VERSION 5.7 ;
  NOWIREEXTENSIONATPIN ON ;
  DIVIDERCHAR "/" ;
  BUSBITCHARS "[]" ;
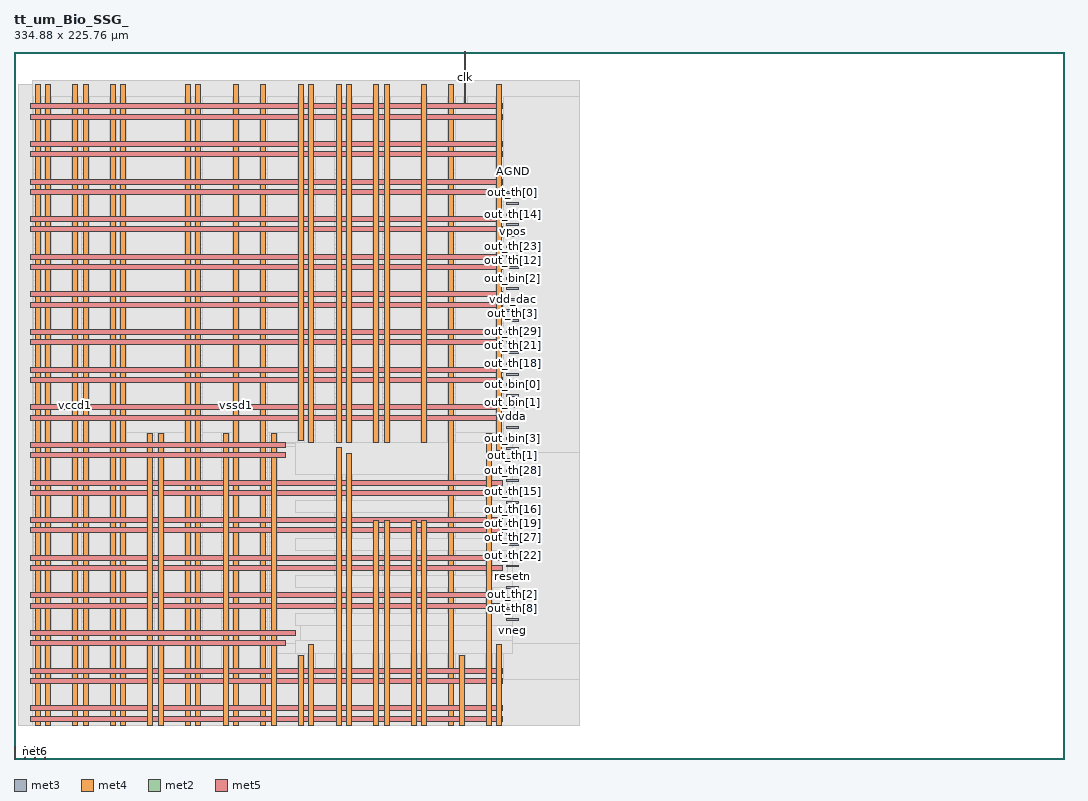
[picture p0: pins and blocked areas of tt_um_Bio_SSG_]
MACRO tt_um_Bio_SSG_
  CLASS BLOCK ;
  FOREIGN tt_um_Bio_SSG_ ;
  ORIGIN 0.000 0.000 ;
  SIZE 334.880 BY 225.760 ;
  PIN AGND
    DIRECTION INOUT ;
    USE SIGNAL ;
    ANTENNADIFFAREA 0.434700 ;
    PORT
      LAYER met3 ;
        RECT 157.000 187.040 161.000 187.640 ;
    END
  END AGND
  PIN clk
    DIRECTION INPUT ;
    USE SIGNAL ;
    ANTENNAGATEAREA 0.852000 ;
    ANTENNADIFFAREA 0.434700 ;
    PORT
      LAYER met4 ;
        RECT 143.830 208.950 144.130 225.760 ;
    END
  END clk
  PIN cm1
    DIRECTION INOUT ;
    USE SIGNAL ;
    PORT
      LAYER met2 ;
        RECT 0.090 0.000 0.370 4.000 ;
    END
  END cm1
  PIN cm2
    DIRECTION INOUT ;
    USE SIGNAL ;
    PORT
      LAYER met2 ;
        RECT 3.310 0.000 3.590 4.000 ;
    END
  END cm2
  PIN net6
    DIRECTION INOUT ;
    USE SIGNAL ;
    PORT
      LAYER met2 ;
        RECT 6.530 0.000 6.810 4.000 ;
    END
  END net6
  PIN net7
    DIRECTION INOUT ;
    USE SIGNAL ;
    PORT
      LAYER met2 ;
        RECT 9.750 0.000 10.030 4.000 ;
    END
  END net7
  PIN out_bin[0]
    DIRECTION OUTPUT ;
    USE SIGNAL ;
    ANTENNADIFFAREA 0.445500 ;
    PORT
      LAYER met3 ;
        RECT 157.000 119.040 161.000 119.640 ;
    END
  END out_bin[0]
  PIN out_bin[1]
    DIRECTION OUTPUT ;
    USE SIGNAL ;
    ANTENNADIFFAREA 0.445500 ;
    PORT
      LAYER met3 ;
        RECT 157.000 115.640 161.000 116.240 ;
    END
  END out_bin[1]
  PIN out_bin[2]
    DIRECTION OUTPUT ;
    USE SIGNAL ;
    ANTENNADIFFAREA 0.445500 ;
    PORT
      LAYER met3 ;
        RECT 157.000 153.040 161.000 153.640 ;
    END
  END out_bin[2]
  PIN out_bin[3]
    DIRECTION OUTPUT ;
    USE SIGNAL ;
    ANTENNADIFFAREA 0.445500 ;
    PORT
      LAYER met3 ;
        RECT 157.000 102.040 161.000 102.640 ;
    END
  END out_bin[3]
  PIN out_th[0]
    DIRECTION OUTPUT ;
    USE SIGNAL ;
    ANTENNADIFFAREA 0.445500 ;
    PORT
      LAYER met3 ;
        RECT 157.000 180.240 161.000 180.840 ;
    END
  END out_th[0]
  PIN out_th[10]
    DIRECTION OUTPUT ;
    USE SIGNAL ;
    ANTENNADIFFAREA 0.445500 ;
    PORT
      LAYER met3 ;
        RECT 157.000 132.640 161.000 133.240 ;
    END
  END out_th[10]
  PIN out_th[11]
    DIRECTION OUTPUT ;
    USE SIGNAL ;
    ANTENNADIFFAREA 0.445500 ;
    PORT
      LAYER met3 ;
        RECT 157.000 95.240 161.000 95.840 ;
    END
  END out_th[11]
  PIN out_th[12]
    DIRECTION OUTPUT ;
    USE SIGNAL ;
    ANTENNADIFFAREA 0.445500 ;
    PORT
      LAYER met3 ;
        RECT 157.000 156.440 161.000 157.040 ;
    END
  END out_th[12]
  PIN out_th[13]
    DIRECTION OUTPUT ;
    USE SIGNAL ;
    ANTENNADIFFAREA 0.445500 ;
    PORT
      LAYER met3 ;
        RECT 157.000 88.440 161.000 89.040 ;
    END
  END out_th[13]
  PIN out_th[14]
    DIRECTION OUTPUT ;
    USE SIGNAL ;
    ANTENNADIFFAREA 0.445500 ;
    PORT
      LAYER met3 ;
        RECT 157.000 173.440 161.000 174.040 ;
    END
  END out_th[14]
  PIN out_th[15]
    DIRECTION OUTPUT ;
    USE SIGNAL ;
    ANTENNADIFFAREA 0.445500 ;
    PORT
      LAYER met3 ;
        RECT 157.000 85.040 161.000 85.640 ;
    END
  END out_th[15]
  PIN out_th[16]
    DIRECTION OUTPUT ;
    USE SIGNAL ;
    ANTENNADIFFAREA 0.445500 ;
    PORT
      LAYER met3 ;
        RECT 157.000 81.640 161.000 82.240 ;
    END
  END out_th[16]
  PIN out_th[17]
    DIRECTION OUTPUT ;
    USE SIGNAL ;
    ANTENNADIFFAREA 0.445500 ;
    PORT
      LAYER met3 ;
        RECT 157.000 159.840 161.000 160.440 ;
    END
  END out_th[17]
  PIN out_th[18]
    DIRECTION OUTPUT ;
    USE SIGNAL ;
    ANTENNADIFFAREA 0.445500 ;
    PORT
      LAYER met3 ;
        RECT 157.000 125.840 161.000 126.440 ;
    END
  END out_th[18]
  PIN out_th[19]
    DIRECTION OUTPUT ;
    USE SIGNAL ;
    ANTENNADIFFAREA 0.445500 ;
    PORT
      LAYER met3 ;
        RECT 157.000 74.840 161.000 75.440 ;
    END
  END out_th[19]
  PIN out_th[1]
    DIRECTION OUTPUT ;
    USE SIGNAL ;
    ANTENNADIFFAREA 0.445500 ;
    PORT
      LAYER met3 ;
        RECT 157.000 98.640 161.000 99.240 ;
    END
  END out_th[1]
  PIN out_th[20]
    DIRECTION OUTPUT ;
    USE SIGNAL ;
    ANTENNADIFFAREA 0.445500 ;
    PORT
      LAYER met3 ;
        RECT 157.000 112.240 161.000 112.840 ;
    END
  END out_th[20]
  PIN out_th[21]
    DIRECTION OUTPUT ;
    USE SIGNAL ;
    ANTENNADIFFAREA 0.445500 ;
    PORT
      LAYER met3 ;
        RECT 157.000 129.240 161.000 129.840 ;
    END
  END out_th[21]
  PIN out_th[22]
    DIRECTION OUTPUT ;
    USE SIGNAL ;
    ANTENNADIFFAREA 0.445500 ;
    PORT
      LAYER met3 ;
        RECT 157.000 64.640 161.000 65.240 ;
    END
  END out_th[22]
  PIN out_th[23]
    DIRECTION OUTPUT ;
    USE SIGNAL ;
    ANTENNADIFFAREA 0.445500 ;
    PORT
      LAYER met3 ;
        RECT 157.000 163.240 161.000 163.840 ;
    END
  END out_th[23]
  PIN out_th[24]
    DIRECTION OUTPUT ;
    USE SIGNAL ;
    ANTENNADIFFAREA 0.445500 ;
    PORT
      LAYER met3 ;
        RECT 157.000 61.240 161.000 61.840 ;
    END
  END out_th[24]
  PIN out_th[25]
    DIRECTION OUTPUT ;
    USE SIGNAL ;
    ANTENNADIFFAREA 0.445500 ;
    PORT
      LAYER met3 ;
        RECT 157.000 176.840 161.000 177.440 ;
    END
  END out_th[25]
  PIN out_th[26]
    DIRECTION OUTPUT ;
    USE SIGNAL ;
    ANTENNADIFFAREA 0.445500 ;
    PORT
      LAYER met3 ;
        RECT 157.000 78.240 161.000 78.840 ;
    END
  END out_th[26]
  PIN out_th[27]
    DIRECTION OUTPUT ;
    USE SIGNAL ;
    ANTENNADIFFAREA 0.445500 ;
    PORT
      LAYER met3 ;
        RECT 157.000 68.040 161.000 68.640 ;
    END
  END out_th[27]
  PIN out_th[28]
    DIRECTION OUTPUT ;
    USE SIGNAL ;
    ANTENNADIFFAREA 0.445500 ;
    PORT
      LAYER met3 ;
        RECT 157.000 91.840 161.000 92.440 ;
    END
  END out_th[28]
  PIN out_th[29]
    DIRECTION OUTPUT ;
    USE SIGNAL ;
    ANTENNADIFFAREA 0.445500 ;
    PORT
      LAYER met3 ;
        RECT 157.000 136.040 161.000 136.640 ;
    END
  END out_th[29]
  PIN out_th[2]
    DIRECTION OUTPUT ;
    USE SIGNAL ;
    ANTENNADIFFAREA 0.445500 ;
    PORT
      LAYER met3 ;
        RECT 157.000 54.440 161.000 55.040 ;
    END
  END out_th[2]
  PIN out_th[30]
    DIRECTION OUTPUT ;
    USE SIGNAL ;
    ANTENNADIFFAREA 0.445500 ;
    PORT
      LAYER met3 ;
        RECT 157.000 105.440 161.000 106.040 ;
    END
  END out_th[30]
  PIN out_th[31]
    DIRECTION OUTPUT ;
    USE SIGNAL ;
    ANTENNADIFFAREA 0.445500 ;
    PORT
      LAYER met3 ;
        RECT 157.000 51.040 161.000 51.640 ;
    END
  END out_th[31]
  PIN out_th[3]
    DIRECTION OUTPUT ;
    USE SIGNAL ;
    ANTENNADIFFAREA 0.445500 ;
    PORT
      LAYER met3 ;
        RECT 157.000 139.440 161.000 140.040 ;
    END
  END out_th[3]
  PIN out_th[4]
    DIRECTION OUTPUT ;
    USE SIGNAL ;
    ANTENNADIFFAREA 0.445500 ;
    PORT
      LAYER met3 ;
        RECT 157.000 166.640 161.000 167.240 ;
    END
  END out_th[4]
  PIN out_th[5]
    DIRECTION OUTPUT ;
    USE SIGNAL ;
    ANTENNADIFFAREA 0.445500 ;
    PORT
      LAYER met3 ;
        RECT 157.000 71.440 161.000 72.040 ;
    END
  END out_th[5]
  PIN out_th[6]
    DIRECTION OUTPUT ;
    USE SIGNAL ;
    ANTENNADIFFAREA 0.445500 ;
    PORT
      LAYER met3 ;
        RECT 157.000 122.440 161.000 123.040 ;
    END
  END out_th[6]
  PIN out_th[7]
    DIRECTION OUTPUT ;
    USE SIGNAL ;
    ANTENNADIFFAREA 0.445500 ;
    PORT
      LAYER met3 ;
        RECT 157.000 142.840 161.000 143.440 ;
    END
  END out_th[7]
  PIN out_th[8]
    DIRECTION OUTPUT ;
    USE SIGNAL ;
    ANTENNADIFFAREA 0.445500 ;
    PORT
      LAYER met3 ;
        RECT 157.000 47.640 161.000 48.240 ;
    END
  END out_th[8]
  PIN out_th[9]
    DIRECTION OUTPUT ;
    USE SIGNAL ;
    ANTENNADIFFAREA 0.445500 ;
    PORT
      LAYER met3 ;
        RECT 157.000 44.240 161.000 44.840 ;
    END
  END out_th[9]
  PIN resetn
    DIRECTION INPUT ;
    USE SIGNAL ;
    ANTENNAGATEAREA 0.196500 ;
    ANTENNADIFFAREA 0.434700 ;
    PORT
      LAYER met3 ;
        RECT 157.000 57.840 161.000 58.440 ;
    END
  END resetn
  PIN vccd1
    DIRECTION INOUT ;
    USE POWER ;
    PORT
      LAYER met4 ;
        RECT 6.720 10.640 8.320 215.120 ;
    END
    PORT
      LAYER met4 ;
        RECT 18.720 10.640 20.320 215.120 ;
    END
    PORT
      LAYER met4 ;
        RECT 30.720 10.640 32.320 215.120 ;
    END
    PORT
      LAYER met4 ;
        RECT 42.720 10.640 44.320 103.720 ;
    END
    PORT
      LAYER met4 ;
        RECT 54.720 10.640 56.320 215.120 ;
    END
    PORT
      LAYER met4 ;
        RECT 66.720 10.640 68.320 103.720 ;
    END
    PORT
      LAYER met4 ;
        RECT 78.720 10.640 80.320 215.120 ;
    END
    PORT
      LAYER met4 ;
        RECT 90.720 10.640 92.320 33.160 ;
    END
    PORT
      LAYER met4 ;
        RECT 90.720 101.480 92.320 215.120 ;
    END
    PORT
      LAYER met4 ;
        RECT 102.720 10.640 104.320 99.405 ;
    END
    PORT
      LAYER met4 ;
        RECT 102.720 100.935 104.320 215.120 ;
    END
    PORT
      LAYER met4 ;
        RECT 114.720 10.640 116.320 76.120 ;
    END
    PORT
      LAYER met4 ;
        RECT 114.720 100.935 116.320 215.120 ;
    END
    PORT
      LAYER met4 ;
        RECT 126.720 10.640 128.320 76.120 ;
    END
    PORT
      LAYER met4 ;
        RECT 138.720 10.640 140.320 215.120 ;
    END
    PORT
      LAYER met4 ;
        RECT 150.720 10.640 152.320 103.720 ;
    END
    PORT
      LAYER met5 ;
        RECT 5.280 12.080 155.720 13.680 ;
    END
    PORT
      LAYER met5 ;
        RECT 5.280 24.080 155.720 25.680 ;
    END
    PORT
      LAYER met5 ;
        RECT 5.280 36.080 86.620 37.680 ;
    END
    PORT
      LAYER met5 ;
        RECT 5.280 48.080 155.720 49.680 ;
    END
    PORT
      LAYER met5 ;
        RECT 5.280 60.080 155.720 61.680 ;
    END
    PORT
      LAYER met5 ;
        RECT 5.280 72.080 155.720 73.680 ;
    END
    PORT
      LAYER met5 ;
        RECT 5.280 84.080 155.720 85.680 ;
    END
    PORT
      LAYER met5 ;
        RECT 5.280 96.080 86.620 97.680 ;
    END
    PORT
      LAYER met5 ;
        RECT 5.280 108.080 155.720 109.680 ;
    END
    PORT
      LAYER met5 ;
        RECT 5.280 120.080 155.720 121.680 ;
    END
    PORT
      LAYER met5 ;
        RECT 5.280 132.080 155.720 133.680 ;
    END
    PORT
      LAYER met5 ;
        RECT 5.280 144.080 155.720 145.680 ;
    END
    PORT
      LAYER met5 ;
        RECT 5.280 156.080 155.720 157.680 ;
    END
    PORT
      LAYER met5 ;
        RECT 5.280 168.080 155.720 169.680 ;
    END
    PORT
      LAYER met5 ;
        RECT 5.280 180.080 155.720 181.680 ;
    END
    PORT
      LAYER met5 ;
        RECT 5.280 192.080 155.720 193.680 ;
    END
    PORT
      LAYER met5 ;
        RECT 5.280 204.080 155.720 205.680 ;
    END
  END vccd1
  PIN vdd_dac
    DIRECTION INOUT ;
    USE SIGNAL ;
    ANTENNADIFFAREA 0.434700 ;
    PORT
      LAYER met3 ;
        RECT 157.000 146.240 161.000 146.840 ;
    END
  END vdd_dac
  PIN vdda
    DIRECTION INOUT ;
    USE SIGNAL ;
    PORT
      LAYER met3 ;
        RECT 157.000 108.840 161.000 109.440 ;
    END
  END vdda
  PIN vneg
    DIRECTION OUTPUT ;
    USE SIGNAL ;
    ANTENNADIFFAREA 0.445500 ;
    PORT
      LAYER met3 ;
        RECT 157.000 40.840 161.000 41.440 ;
    END
  END vneg
  PIN vpos
    DIRECTION OUTPUT ;
    USE SIGNAL ;
    ANTENNADIFFAREA 0.445500 ;
    PORT
      LAYER met3 ;
        RECT 157.000 170.040 161.000 170.640 ;
    END
  END vpos
  PIN vss
    DIRECTION INOUT ;
    USE SIGNAL ;
    ANTENNADIFFAREA 0.869400 ;
    PORT
      LAYER met3 ;
        RECT 157.000 149.640 161.000 150.240 ;
    END
  END vss
  PIN vssd1
    DIRECTION INOUT ;
    USE GROUND ;
    PORT
      LAYER met4 ;
        RECT 10.020 10.640 11.620 215.120 ;
    END
    PORT
      LAYER met4 ;
        RECT 22.020 10.640 23.620 215.120 ;
    END
    PORT
      LAYER met4 ;
        RECT 34.020 10.640 35.620 215.120 ;
    END
    PORT
      LAYER met4 ;
        RECT 46.020 10.640 47.620 103.720 ;
    END
    PORT
      LAYER met4 ;
        RECT 58.020 10.640 59.620 215.120 ;
    END
    PORT
      LAYER met4 ;
        RECT 70.020 10.640 71.620 215.120 ;
    END
    PORT
      LAYER met4 ;
        RECT 82.020 10.640 83.620 103.720 ;
    END
    PORT
      LAYER met4 ;
        RECT 94.020 10.640 95.620 36.360 ;
    END
    PORT
      LAYER met4 ;
        RECT 94.020 100.935 95.620 215.120 ;
    END
    PORT
      LAYER met4 ;
        RECT 106.020 10.640 107.620 97.570 ;
    END
    PORT
      LAYER met4 ;
        RECT 106.020 100.935 107.620 215.120 ;
    END
    PORT
      LAYER met4 ;
        RECT 118.020 10.640 119.620 76.120 ;
    END
    PORT
      LAYER met4 ;
        RECT 118.020 100.935 119.620 215.120 ;
    END
    PORT
      LAYER met4 ;
        RECT 130.020 10.640 131.620 76.120 ;
    END
    PORT
      LAYER met4 ;
        RECT 130.020 100.935 131.620 215.120 ;
    END
    PORT
      LAYER met4 ;
        RECT 142.020 10.640 143.620 33.160 ;
    END
    PORT
      LAYER met4 ;
        RECT 154.020 10.640 155.620 36.360 ;
    END
    PORT
      LAYER met4 ;
        RECT 154.020 98.280 155.620 215.120 ;
    END
    PORT
      LAYER met5 ;
        RECT 5.280 15.380 155.720 16.980 ;
    END
    PORT
      LAYER met5 ;
        RECT 5.280 27.380 155.720 28.980 ;
    END
    PORT
      LAYER met5 ;
        RECT 5.280 39.380 89.820 40.980 ;
    END
    PORT
      LAYER met5 ;
        RECT 5.280 51.380 155.720 52.980 ;
    END
    PORT
      LAYER met5 ;
        RECT 5.280 63.380 155.720 64.980 ;
    END
    PORT
      LAYER met5 ;
        RECT 5.280 75.380 155.720 76.980 ;
    END
    PORT
      LAYER met5 ;
        RECT 5.280 87.380 155.720 88.980 ;
    END
    PORT
      LAYER met5 ;
        RECT 5.280 99.380 86.620 100.980 ;
    END
    PORT
      LAYER met5 ;
        RECT 5.280 111.380 155.720 112.980 ;
    END
    PORT
      LAYER met5 ;
        RECT 5.280 123.380 155.720 124.980 ;
    END
    PORT
      LAYER met5 ;
        RECT 5.280 135.380 155.720 136.980 ;
    END
    PORT
      LAYER met5 ;
        RECT 5.280 147.380 155.720 148.980 ;
    END
    PORT
      LAYER met5 ;
        RECT 5.280 159.380 155.720 160.980 ;
    END
    PORT
      LAYER met5 ;
        RECT 5.280 171.380 155.720 172.980 ;
    END
    PORT
      LAYER met5 ;
        RECT 5.280 183.380 155.720 184.980 ;
    END
    PORT
      LAYER met5 ;
        RECT 5.280 195.380 155.720 196.980 ;
    END
    PORT
      LAYER met5 ;
        RECT 5.280 207.380 155.720 208.980 ;
    END
  END vssd1
  OBS
      LAYER li1 ;
        RECT 5.520 10.795 155.480 214.965 ;
      LAYER met1 ;
        RECT 1.450 10.640 159.550 215.120 ;
      LAYER met2 ;
        RECT 1.480 10.695 160.910 215.065 ;
      LAYER met3 ;
        RECT 5.790 188.040 180.380 216.305 ;
        RECT 5.790 186.640 156.600 188.040 ;
        RECT 161.400 186.640 180.380 188.040 ;
        RECT 5.790 181.240 180.380 186.640 ;
        RECT 5.790 179.840 156.600 181.240 ;
        RECT 161.400 179.840 180.380 181.240 ;
        RECT 5.790 177.840 180.380 179.840 ;
        RECT 5.790 176.440 156.600 177.840 ;
        RECT 161.400 176.440 180.380 177.840 ;
        RECT 5.790 174.440 180.380 176.440 ;
        RECT 5.790 173.040 156.600 174.440 ;
        RECT 161.400 173.040 180.380 174.440 ;
        RECT 5.790 171.040 180.380 173.040 ;
        RECT 5.790 169.640 156.600 171.040 ;
        RECT 161.400 169.640 180.380 171.040 ;
        RECT 5.790 167.640 180.380 169.640 ;
        RECT 5.790 166.240 156.600 167.640 ;
        RECT 161.400 166.240 180.380 167.640 ;
        RECT 5.790 164.240 180.380 166.240 ;
        RECT 5.790 162.840 156.600 164.240 ;
        RECT 161.400 162.840 180.380 164.240 ;
        RECT 5.790 160.840 180.380 162.840 ;
        RECT 5.790 159.440 156.600 160.840 ;
        RECT 161.400 159.440 180.380 160.840 ;
        RECT 5.790 157.440 180.380 159.440 ;
        RECT 5.790 156.040 156.600 157.440 ;
        RECT 161.400 156.040 180.380 157.440 ;
        RECT 5.790 154.040 180.380 156.040 ;
        RECT 5.790 152.640 156.600 154.040 ;
        RECT 161.400 152.640 180.380 154.040 ;
        RECT 5.790 150.640 180.380 152.640 ;
        RECT 5.790 149.240 156.600 150.640 ;
        RECT 161.400 149.240 180.380 150.640 ;
        RECT 5.790 147.240 180.380 149.240 ;
        RECT 5.790 145.840 156.600 147.240 ;
        RECT 161.400 145.840 180.380 147.240 ;
        RECT 5.790 143.840 180.380 145.840 ;
        RECT 5.790 142.440 156.600 143.840 ;
        RECT 161.400 142.440 180.380 143.840 ;
        RECT 5.790 140.440 180.380 142.440 ;
        RECT 5.790 139.040 156.600 140.440 ;
        RECT 161.400 139.040 180.380 140.440 ;
        RECT 5.790 137.040 180.380 139.040 ;
        RECT 5.790 135.640 156.600 137.040 ;
        RECT 161.400 135.640 180.380 137.040 ;
        RECT 5.790 133.640 180.380 135.640 ;
        RECT 5.790 132.240 156.600 133.640 ;
        RECT 161.400 132.240 180.380 133.640 ;
        RECT 5.790 130.240 180.380 132.240 ;
        RECT 5.790 128.840 156.600 130.240 ;
        RECT 161.400 128.840 180.380 130.240 ;
        RECT 5.790 126.840 180.380 128.840 ;
        RECT 5.790 125.440 156.600 126.840 ;
        RECT 161.400 125.440 180.380 126.840 ;
        RECT 5.790 123.440 180.380 125.440 ;
        RECT 5.790 122.040 156.600 123.440 ;
        RECT 161.400 122.040 180.380 123.440 ;
        RECT 5.790 120.040 180.380 122.040 ;
        RECT 5.790 118.640 156.600 120.040 ;
        RECT 161.400 118.640 180.380 120.040 ;
        RECT 5.790 116.640 180.380 118.640 ;
        RECT 5.790 115.240 156.600 116.640 ;
        RECT 161.400 115.240 180.380 116.640 ;
        RECT 5.790 113.240 180.380 115.240 ;
        RECT 5.790 111.840 156.600 113.240 ;
        RECT 161.400 111.840 180.380 113.240 ;
        RECT 5.790 109.840 180.380 111.840 ;
        RECT 5.790 108.440 156.600 109.840 ;
        RECT 161.400 108.440 180.380 109.840 ;
        RECT 5.790 106.440 180.380 108.440 ;
        RECT 5.790 105.040 156.600 106.440 ;
        RECT 161.400 105.040 180.380 106.440 ;
        RECT 5.790 103.040 180.380 105.040 ;
        RECT 5.790 101.640 156.600 103.040 ;
        RECT 161.400 101.640 180.380 103.040 ;
        RECT 5.790 99.640 180.380 101.640 ;
        RECT 5.790 98.240 156.600 99.640 ;
        RECT 161.400 98.240 180.380 99.640 ;
        RECT 5.790 96.240 180.380 98.240 ;
        RECT 5.790 94.840 156.600 96.240 ;
        RECT 161.400 94.840 180.380 96.240 ;
        RECT 5.790 92.840 180.380 94.840 ;
        RECT 5.790 91.440 156.600 92.840 ;
        RECT 161.400 91.440 180.380 92.840 ;
        RECT 5.790 89.440 180.380 91.440 ;
        RECT 5.790 88.040 156.600 89.440 ;
        RECT 161.400 88.040 180.380 89.440 ;
        RECT 5.790 86.040 180.380 88.040 ;
        RECT 5.790 84.640 156.600 86.040 ;
        RECT 161.400 84.640 180.380 86.040 ;
        RECT 5.790 82.640 180.380 84.640 ;
        RECT 5.790 81.240 156.600 82.640 ;
        RECT 161.400 81.240 180.380 82.640 ;
        RECT 5.790 79.240 180.380 81.240 ;
        RECT 5.790 77.840 156.600 79.240 ;
        RECT 161.400 77.840 180.380 79.240 ;
        RECT 5.790 75.840 180.380 77.840 ;
        RECT 5.790 74.440 156.600 75.840 ;
        RECT 161.400 74.440 180.380 75.840 ;
        RECT 5.790 72.440 180.380 74.440 ;
        RECT 5.790 71.040 156.600 72.440 ;
        RECT 161.400 71.040 180.380 72.440 ;
        RECT 5.790 69.040 180.380 71.040 ;
        RECT 5.790 67.640 156.600 69.040 ;
        RECT 161.400 67.640 180.380 69.040 ;
        RECT 5.790 65.640 180.380 67.640 ;
        RECT 5.790 64.240 156.600 65.640 ;
        RECT 161.400 64.240 180.380 65.640 ;
        RECT 5.790 62.240 180.380 64.240 ;
        RECT 5.790 60.840 156.600 62.240 ;
        RECT 161.400 60.840 180.380 62.240 ;
        RECT 5.790 58.840 180.380 60.840 ;
        RECT 5.790 57.440 156.600 58.840 ;
        RECT 161.400 57.440 180.380 58.840 ;
        RECT 5.790 55.440 180.380 57.440 ;
        RECT 5.790 54.040 156.600 55.440 ;
        RECT 161.400 54.040 180.380 55.440 ;
        RECT 5.790 52.040 180.380 54.040 ;
        RECT 5.790 50.640 156.600 52.040 ;
        RECT 161.400 50.640 180.380 52.040 ;
        RECT 5.790 48.640 180.380 50.640 ;
        RECT 5.790 47.240 156.600 48.640 ;
        RECT 161.400 47.240 180.380 48.640 ;
        RECT 5.790 45.240 180.380 47.240 ;
        RECT 5.790 43.840 156.600 45.240 ;
        RECT 161.400 43.840 180.380 45.240 ;
        RECT 5.790 41.840 180.380 43.840 ;
        RECT 5.790 40.440 156.600 41.840 ;
        RECT 161.400 40.440 180.380 41.840 ;
        RECT 5.790 10.715 180.380 40.440 ;
      LAYER met4 ;
        RECT 5.815 25.335 6.320 211.200 ;
        RECT 8.720 25.335 9.620 211.200 ;
        RECT 12.020 25.335 18.320 211.200 ;
        RECT 20.720 25.335 21.620 211.200 ;
        RECT 24.020 25.335 30.320 211.200 ;
        RECT 32.720 25.335 33.620 211.200 ;
        RECT 36.020 104.120 54.320 211.200 ;
        RECT 36.020 25.335 42.320 104.120 ;
        RECT 44.720 25.335 45.620 104.120 ;
        RECT 48.020 25.335 54.320 104.120 ;
        RECT 56.720 25.335 57.620 211.200 ;
        RECT 60.020 104.120 69.620 211.200 ;
        RECT 60.020 25.335 66.320 104.120 ;
        RECT 68.720 25.335 69.620 104.120 ;
        RECT 72.020 25.335 78.320 211.200 ;
        RECT 80.720 104.120 90.320 211.200 ;
        RECT 80.720 25.335 81.620 104.120 ;
        RECT 84.020 101.080 90.320 104.120 ;
        RECT 92.720 101.080 93.620 211.200 ;
        RECT 84.020 100.535 93.620 101.080 ;
        RECT 96.020 100.535 102.320 211.200 ;
        RECT 104.720 100.535 105.620 211.200 ;
        RECT 108.020 100.535 114.320 211.200 ;
        RECT 116.720 100.535 117.620 211.200 ;
        RECT 120.020 100.535 129.620 211.200 ;
        RECT 132.020 100.535 138.320 211.200 ;
        RECT 84.020 99.805 138.320 100.535 ;
        RECT 84.020 36.760 102.320 99.805 ;
        RECT 84.020 33.560 93.620 36.760 ;
        RECT 84.020 25.335 90.320 33.560 ;
        RECT 92.720 25.335 93.620 33.560 ;
        RECT 96.020 25.335 102.320 36.760 ;
        RECT 104.720 97.970 138.320 99.805 ;
        RECT 104.720 25.335 105.620 97.970 ;
        RECT 108.020 76.520 138.320 97.970 ;
        RECT 108.020 25.335 114.320 76.520 ;
        RECT 116.720 25.335 117.620 76.520 ;
        RECT 120.020 25.335 126.320 76.520 ;
        RECT 128.720 25.335 129.620 76.520 ;
        RECT 132.020 25.335 138.320 76.520 ;
        RECT 140.720 208.550 143.430 211.200 ;
        RECT 144.530 208.550 153.620 211.200 ;
        RECT 140.720 104.120 153.620 208.550 ;
        RECT 140.720 33.560 150.320 104.120 ;
        RECT 140.720 25.335 141.620 33.560 ;
        RECT 144.020 25.335 150.320 33.560 ;
        RECT 152.720 97.880 153.620 104.120 ;
        RECT 156.020 97.880 180.380 211.200 ;
        RECT 152.720 36.760 180.380 97.880 ;
        RECT 152.720 25.335 153.620 36.760 ;
        RECT 156.020 25.335 180.380 36.760 ;
      LAYER met5 ;
        RECT 89.820 90.580 158.960 100.880 ;
        RECT 157.320 82.480 158.960 90.580 ;
        RECT 89.820 78.580 158.960 82.480 ;
        RECT 157.320 70.480 158.960 78.580 ;
        RECT 89.820 66.580 158.960 70.480 ;
        RECT 157.320 58.480 158.960 66.580 ;
        RECT 89.820 54.580 158.960 58.480 ;
        RECT 157.320 46.480 158.960 54.580 ;
        RECT 89.820 42.580 158.960 46.480 ;
        RECT 91.420 37.780 158.960 42.580 ;
        RECT 89.820 33.760 158.960 37.780 ;
  END
END tt_um_Bio_SSG_
END LIBRARY

